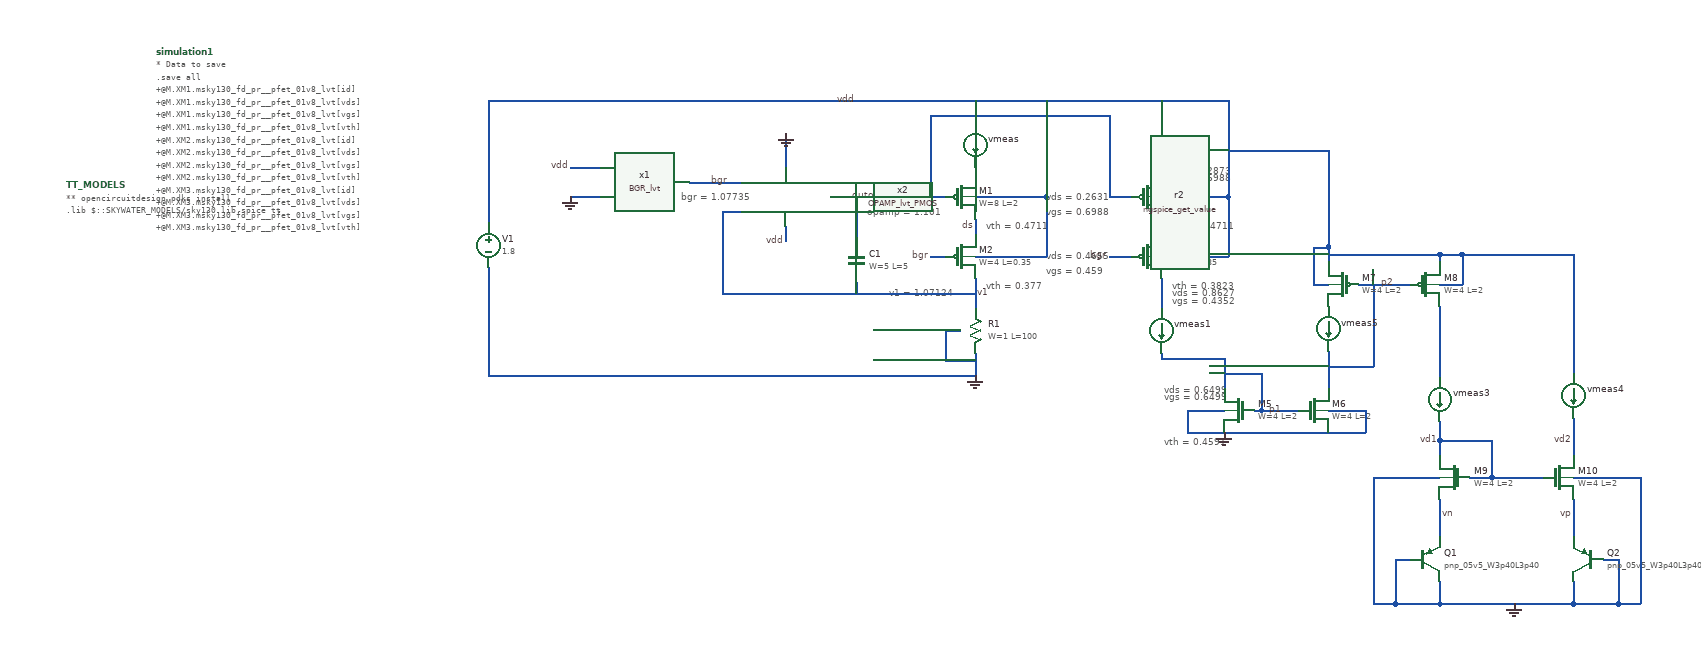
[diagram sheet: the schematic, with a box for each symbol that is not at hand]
v {xschem version=3.1.0 file_version=1.2
}
G {}
K {}
V {}
S {}
E {}
T {bgr = 1.07735} 1030 -690 0 0 0.2 0.2 {}
T {opamp = 1.101} 1280 -670 0 0 0.2 0.2 {}
T {vth = 0.4711} 1440 -650 0 0 0.2 0.2 {}
T {vth = 0.377} 1440 -570 0 0 0.2 0.2 {}
T {vth = 0.4711} 1690 -650 0 0 0.2 0.2 {}
T {vth = 0.3823} 1690 -570 0 0 0.2 0.2 {}
T {vds = 0.2631} 1520 -690 0 0 0.2 0.2 {}
T {vgs = 0.6988} 1520 -670 0 0 0.2 0.2 {}
T {vds = 0.4655} 1520 -610 0 0 0.2 0.2 {}
T {vgs = 0.459} 1520 -590 0 0 0.2 0.2 {}
T {vds = 0.2873} 1685 -725 0 0 0.2 0.2 {}
T {vgs = 0.6988} 1685 -715 0 0 0.2 0.2 {}
T {vds = 0.8627} 1690 -560 0 0 0.2 0.2 {}
T {vgs = 0.4352} 1690 -550 0 0 0.2 0.2 {}
T {v1 = 1.07124} 1310 -560 0 0 0.2 0.2 {}
T {vth = 0.4591} 1680 -360 0 0 0.2 0.2 {}
T {vgs = 0.6499} 1680 -420 0 0 0.2 0.2 {}
T {vds = 0.6499} 1680 -430 0 0 0.2 0.2 {}
N 1070 -697.5 1110 -697.5 {
lab=bgr}
N 1085 -657.5 1110 -657.5 {
lab=v1}
N 880 -677.5 890 -677.5 {
lab=GND}
N 880 -717.5 890 -717.5 {
lab=vdd}
N 1425 -722.5 1425 -707.5 {
lab=#net1}
N 1230 -677.5 1385 -677.5 {
lab=outop}
N 1425 -807.5 1425 -777.5 {
lab=vdd}
N 1425 -647.5 1425 -627.5 {
lab=ds}
N 1425 -567.5 1425 -527.5 {
lab=v1}
N 1085 -547.5 1425 -547.5 {
lab=v1}
N 1085 -657.5 1085 -547.5 {
lab=v1}
N 1265 -677.5 1265 -622.5 {
lab=outop}
N 1265 -562.5 1265 -547.5 {
lab=v1}
N 1425 -677.5 1520 -677.5 {
lab=vdd}
N 1520 -807.5 1520 -677.5 {
lab=vdd}
N 1425 -597.5 1520 -597.5 {
lab=vdd}
N 1520 -677.5 1520 -597.5 {
lab=vdd}
N 770 -437.5 1425 -437.5 {
lab=GND}
N 770 -582.5 770 -437.5 {
lab=GND}
N 1365 -597.5 1385 -597.5 {
lab=bgr}
N 1425 -467.5 1425 -437.5 {
lab=GND}
N 1170 -637.5 1170 -617.5 {
lab=vdd}
N 1170 -762.5 1170 -717.5 {
lab=GND}
N 1385 -497.5 1405 -497.5 {
lab=GND}
N 1385 -497.5 1385 -457.5 {
lab=GND}
N 1385 -457.5 1425 -457.5 {
lab=GND}
N 1365 -787.5 1365 -677.5 {
lab=outop}
N 1365 -787.5 1605 -787.5 {
lab=outop}
N 1605 -787.5 1605 -677.5 {
lab=outop}
N 1605 -677.5 1635 -677.5 {
lab=outop}
N 1605 -597.5 1635 -597.5 {
lab=bgr}
N 1675 -647.5 1675 -627.5 {
lab=#net2}
N 1675 -567.5 1675 -527.5 {
lab=#net3}
N 1675 -807.5 1675 -707.5 {
lab=vdd}
N 1675 -597.5 1765 -597.5 {
lab=vdd}
N 1765 -677.5 1765 -597.5 {
lab=vdd}
N 1675 -677.5 1765 -677.5 {
lab=vdd}
N 1765 -807.5 1765 -677.5 {
lab=vdd}
N 770 -807.5 1765 -807.5 {
lab=vdd}
N 770 -807.5 770 -642.5 {
lab=vdd}
N 890 -717.5 920 -717.5 {
lab=vdd}
N 890 -677.5 920 -677.5 {
lab=GND}
N 1040 -697.5 1070 -697.5 {
lab=bgr}
N 2120 -300 2190 -300 {
lab=vd1}
N 2050 -350 2120 -350 {
lab=vd1}
N 2120 -350 2120 -300 {
lab=vd1}
N 2050 -250 2050 -220 {
lab=vn}
N 2230 -250 2230 -220 {
lab=vp}
N 2230 -380 2230 -330 {
lab=vd2}
N 2050 -160 2050 -130 {
lab=GND}
N 2050 -130 2230 -130 {
lab=GND}
N 2230 -160 2230 -130 {
lab=GND}
N 1990 -190 2010 -190 {
lab=GND}
N 1990 -190 1990 -130 {
lab=GND}
N 1990 -130 2050 -130 {
lab=GND}
N 2270 -190 2290 -190 {
lab=GND}
N 2290 -190 2290 -130 {
lab=GND}
N 2230 -130 2290 -130 {
lab=GND}
N 1960 -300 2050 -300 {
lab=GND}
N 1960 -300 1960 -130 {
lab=GND}
N 1960 -130 1990 -130 {
lab=GND}
N 2230 -300 2320 -300 {
lab=GND}
N 2320 -300 2320 -130 {
lab=GND}
N 2290 -130 2320 -130 {
lab=GND}
N 2230 -460 2230 -440 {
lab=vdd}
N 2050 -470 2050 -435 {
lab=#net4}
N 2050 -350 2050 -330 {
lab=vd1}
N 2050 -375 2050 -350 {
lab=vd1}
N 2090 -300 2120 -300 {
lab=vd1}
N 2230 -270 2230 -250 {
lab=vp}
N 2050 -270 2050 -250 {
lab=vn}
N 1760 -460 1760 -420 {
lab=p1}
N 1760 -440 1810 -440 {
lab=p1}
N 1810 -440 1810 -390 {
lab=p1}
N 1800 -390 1810 -390 {
lab=p1}
N 1810 -390 1860 -390 {
lab=p1}
N 1760 -360 1900 -360 {
lab=GND}
N 1900 -470 1900 -420 {
lab=p2}
N 1940 -560 2010 -560 {
lab=p2}
N 1900 -450 1960 -450 {
lab=p2}
N 1960 -500 1960 -450 {
lab=p2}
N 1900 -610 1900 -590 {
lab=vdd}
N 1900 -600 2050 -600 {
lab=vdd}
N 2050 -600 2050 -590 {
lab=vdd}
N 1880 -560 1900 -560 {
lab=vdd}
N 1880 -610 1880 -560 {
lab=vdd}
N 1880 -610 1900 -610 {
lab=vdd}
N 2050 -560 2080 -560 {
lab=vdd}
N 2080 -600 2080 -560 {
lab=vdd}
N 2050 -600 2080 -600 {
lab=vdd}
N 1710 -390 1760 -390 {
lab=GND}
N 1710 -390 1710 -360 {
lab=GND}
N 1710 -360 1760 -360 {
lab=GND}
N 1900 -390 1950 -390 {
lab=GND}
N 1950 -390 1950 -360 {
lab=GND}
N 1900 -360 1950 -360 {
lab=GND}
N 1960 -560 1960 -500 {
lab=p2}
N 2050 -530 2050 -470 {
lab=#net4}
N 1675 -460 1760 -460 {
lab=p1}
N 1675 -467.5 1675 -460 {
lab=p1}
N 1765 -740 1900 -740 {
lab=vdd}
N 1900 -740 1900 -610 {
lab=vdd}
N 2230 -600 2230 -460 {
lab=vdd}
N 2080 -600 2230 -600 {
lab=vdd}
C {devices/vsource.sym} 770 -612.5 0 0 {name=V1 value=1.8}
C {devices/gnd.sym} 1425 -437.5 0 0 {name=l1 lab=GND}
C {devices/ammeter.sym} 1425 -747.5 0 0 {name=vmeas}
C {sky130_fd_pr/cap_mim_m3_1.sym} 1265 -592.5 0 1 {name=C1 model=cap_mim_m3_1 W=5 L=5 MF=1 spiceprefix=X}
C {devices/lab_pin.sym} 1265 -807.5 1 0 {name=p1 sig_type=std_logic lab=vdd}
C {devices/lab_pin.sym} 1425 -547.5 2 0 {name=p2 sig_type=std_logic lab=v1}
C {sky130_fd_pr/pfet_01v8_lvt.sym} 1405 -677.5 0 0 {name=M1
L=2
W=8
nf=1
mult=1
ad="'int((nf+1)/2) * W/nf * 0.29'" 
pd="'2*int((nf+1)/2) * (W/nf + 0.29)'"
as="'int((nf+2)/2) * W/nf * 0.29'" 
ps="'2*int((nf+2)/2) * (W/nf + 0.29)'"
nrd="'0.29 / W'" nrs="'0.29 / W'"
sa=0 sb=0 sd=0
model=pfet_01v8_lvt
spiceprefix=X
}
C {sky130_fd_pr/pfet_01v8_lvt.sym} 1405 -597.5 0 0 {name=M2
L=0.35
W=4
nf=1
mult=1
ad="'int((nf+1)/2) * W/nf * 0.29'" 
pd="'2*int((nf+1)/2) * (W/nf + 0.29)'"
as="'int((nf+2)/2) * W/nf * 0.29'" 
ps="'2*int((nf+2)/2) * (W/nf + 0.29)'"
nrd="'0.29 / W'" nrs="'0.29 / W'"
sa=0 sb=0 sd=0
model=pfet_01v8_lvt
spiceprefix=X
}
C {devices/lab_pin.sym} 1300 -677.5 1 0 {name=p3 sig_type=std_logic lab=outop}
C {devices/lab_pin.sym} 1425 -637.5 0 0 {name=p4 sig_type=std_logic lab=ds}
C {devices/lab_pin.sym} 1095 -697.5 1 0 {name=p5 sig_type=std_logic lab=bgr}
C {sky130_fd_pr/res_xhigh_po.sym} 1425 -497.5 0 0 {name=R1
W=1
L=100
model=res_xhigh_po
spiceprefix=X
mult=1}
C {sky130_fd_pr/pfet_01v8_lvt.sym} 1655 -677.5 0 0 {name=M3
L=2
W=16
nf=2
mult=1
ad="'int((nf+1)/2) * W/nf * 0.29'" 
pd="'2*int((nf+1)/2) * (W/nf + 0.29)'"
as="'int((nf+2)/2) * W/nf * 0.29'" 
ps="'2*int((nf+2)/2) * (W/nf + 0.29)'"
nrd="'0.29 / W'" nrs="'0.29 / W'"
sa=0 sb=0 sd=0
model=pfet_01v8_lvt
spiceprefix=X
}
C {sky130_fd_pr/pfet_01v8_lvt.sym} 1655 -597.5 0 0 {name=M4
L=0.35
W=4
nf=1
mult=2
ad="'int((nf+1)/2) * W/nf * 0.29'" 
pd="'2*int((nf+1)/2) * (W/nf + 0.29)'"
as="'int((nf+2)/2) * W/nf * 0.29'" 
ps="'2*int((nf+2)/2) * (W/nf + 0.29)'"
nrd="'0.29 / W'" nrs="'0.29 / W'"
sa=0 sb=0 sd=0
model=pfet_01v8_lvt
spiceprefix=X
}
C {devices/ammeter.sym} 1675 -497.5 0 0 {name=vmeas1}
C {devices/gnd.sym} 880 -677.5 0 0 {name=l3 lab=GND}
C {devices/gnd.sym} 1170 -762.5 1 0 {name=l4 lab=GND}
C {devices/lab_pin.sym} 1170 -617.5 0 0 {name=p7 sig_type=std_logic lab=vdd}
C {devices/lab_pin.sym} 880 -717.5 0 0 {name=p8 sig_type=std_logic lab=vdd}
C {devices/lab_pin.sym} 1365 -597.5 1 0 {name=p9 sig_type=std_logic lab=bgr}
C {devices/lab_pin.sym} 1605 -597.5 1 0 {name=p10 sig_type=std_logic lab=bgr}
C {Documentos/TESIS DE GRADO/WORK_IN_PROGRESS/My_xschem/BGR_lvt.sym} 980 -697.5 0 0 {name=x1}
C {Documentos/TESIS DE GRADO/WORK_IN_PROGRESS/My_xschem/OPAMP_lvt_PMOS.sym} 1160 -677.5 2 1 {name=x2}
C {devices/code_shown.sym} 322.5 -872.5 0 0 {name=simulation1 only_toplevel=false 
value="* Data to save
.save all
+@M.XM1.msky130_fd_pr__pfet_01v8_lvt[id]
+@M.XM1.msky130_fd_pr__pfet_01v8_lvt[vds]
+@M.XM1.msky130_fd_pr__pfet_01v8_lvt[vgs]
+@M.XM1.msky130_fd_pr__pfet_01v8_lvt[vth]
+@M.XM2.msky130_fd_pr__pfet_01v8_lvt[id]
+@M.XM2.msky130_fd_pr__pfet_01v8_lvt[vds]
+@M.XM2.msky130_fd_pr__pfet_01v8_lvt[vgs]
+@M.XM2.msky130_fd_pr__pfet_01v8_lvt[vth]
+@M.XM3.msky130_fd_pr__pfet_01v8_lvt[id]
+@M.XM3.msky130_fd_pr__pfet_01v8_lvt[vds]
+@M.XM3.msky130_fd_pr__pfet_01v8_lvt[vgs]
+@M.XM3.msky130_fd_pr__pfet_01v8_lvt[vth]
+@M.XM4.msky130_fd_pr__pfet_01v8_lvt[id]
+@M.XM4.msky130_fd_pr__pfet_01v8_lvt[vds]
+@M.XM4.msky130_fd_pr__pfet_01v8_lvt[vgs]
+@M.XM4.msky130_fd_pr__pfet_01v8_lvt[vth]
+@M.XM5.msky130_fd_pr__nfet_01v8_lvt[id]
+@M.XM5.msky130_fd_pr__nfet_01v8_lvt[vds]
+@M.XM5.msky130_fd_pr__nfet_01v8_lvt[vgs]
+@M.XM5.msky130_fd_pr__nfet_01v8_lvt[vth]

.op
.save all
"}
C {devices/code.sym} 202.5 -692.5 0 0 {name=TT_MODELS
only_toplevel=true
format="tcleval( @value )"
value="
** opencircuitdesign pdks install
.lib $::SKYWATER_MODELS/sky130.lib.spice tt

"
spice_ignore=false}
C {devices/launcher.sym} 415 -370 0 0 {name=h1
descr=Backannotate
 tclcommand="xschem annotate_op"}
C {devices/gnd.sym} 2150 -130 0 0 {name=l2 lab=GND}
C {sky130_fd_pr/nfet_01v8_lvt.sym} 2070 -300 0 1 {name=M9
L=2
W=4
nf=2
mult=1
ad="'int((nf+1)/2) * W/nf * 0.29'" 
pd="'2*int((nf+1)/2) * (W/nf + 0.29)'"
as="'int((nf+2)/2) * W/nf * 0.29'" 
ps="'2*int((nf+2)/2) * (W/nf + 0.29)'"
nrd="'0.29 / W'" nrs="'0.29 / W'"
sa=0 sb=0 sd=0
model=nfet_01v8_lvt
spiceprefix=X
}
C {sky130_fd_pr/pnp_05v5.sym} 2030 -190 0 0 {name=Q1
model=pnp_05v5_W3p40L3p40
m=1
spiceprefix=X
}
C {sky130_fd_pr/nfet_01v8_lvt.sym} 2210 -300 0 0 {name=M10
L=2
W=4
nf=1
mult=10
ad="'int((nf+1)/2) * W/nf * 0.29'" 
pd="'2*int((nf+1)/2) * (W/nf + 0.29)'"
as="'int((nf+2)/2) * W/nf * 0.29'" 
ps="'2*int((nf+2)/2) * (W/nf + 0.29)'"
nrd="'0.29 / W'" nrs="'0.29 / W'"
sa=0 sb=0 sd=0
model=nfet_01v8_lvt
spiceprefix=X
}
C {sky130_fd_pr/pnp_05v5.sym} 2250 -190 0 1 {name=Q2
model=pnp_05v5_W3p40L3p40
m=1
spiceprefix=X
}
C {devices/lab_pin.sym} 2230 -250 0 0 {name=p11 sig_type=std_logic lab=vp}
C {devices/lab_pin.sym} 2050 -250 2 0 {name=p12 sig_type=std_logic lab=vn}
C {devices/ammeter.sym} 2230 -410 0 0 {name=vmeas4}
C {devices/ammeter.sym} 2050 -405 0 0 {name=vmeas3}
C {devices/lab_pin.sym} 2050 -350 0 0 {name=p13 sig_type=std_logic lab=vd1}
C {devices/lab_pin.sym} 2230 -350 0 0 {name=p14 sig_type=std_logic lab=vd2}
C {devices/ngspice_get_value.sym} 2120 -310 0 0 {name=r2 node=v(@M.XM1.msky130_fd_pr__nfet_01v8_lvt[vth])
descr="vth="}
C {sky130_fd_pr/nfet_01v8_lvt.sym} 1780 -390 0 1 {name=M5
L=2
W=4
nf=1
mult=1
ad="'int((nf+1)/2) * W/nf * 0.29'" 
pd="'2*int((nf+1)/2) * (W/nf + 0.29)'"
as="'int((nf+2)/2) * W/nf * 0.29'" 
ps="'2*int((nf+2)/2) * (W/nf + 0.29)'"
nrd="'0.29 / W'" nrs="'0.29 / W'"
sa=0 sb=0 sd=0
model=nfet_01v8_lvt
spiceprefix=X
}
C {devices/gnd.sym} 1760 -360 0 0 {name=l11 lab=GND}
C {sky130_fd_pr/nfet_01v8_lvt.sym} 1880 -390 0 0 {name=M6
L=2
W=4
nf=1
mult=1
ad="'int((nf+1)/2) * W/nf * 0.29'" 
pd="'2*int((nf+1)/2) * (W/nf + 0.29)'"
as="'int((nf+2)/2) * W/nf * 0.29'" 
ps="'2*int((nf+2)/2) * (W/nf + 0.29)'"
nrd="'0.29 / W'" nrs="'0.29 / W'"
sa=0 sb=0 sd=0
model=nfet_01v8_lvt
spiceprefix=X
}
C {sky130_fd_pr/pfet_01v8_lvt.sym} 1920 -560 0 1 {name=M7
L=2
W=4
nf=1
mult=1
ad="'int((nf+1)/2) * W/nf * 0.29'" 
pd="'2*int((nf+1)/2) * (W/nf + 0.29)'"
as="'int((nf+2)/2) * W/nf * 0.29'" 
ps="'2*int((nf+2)/2) * (W/nf + 0.29)'"
nrd="'0.29 / W'" nrs="'0.29 / W'"
sa=0 sb=0 sd=0
model=pfet_01v8_lvt
spiceprefix=X
}
C {sky130_fd_pr/pfet_01v8_lvt.sym} 2030 -560 0 0 {name=M8
L=2
W=4
nf=1
mult=1
ad="'int((nf+1)/2) * W/nf * 0.29'" 
pd="'2*int((nf+1)/2) * (W/nf + 0.29)'"
as="'int((nf+2)/2) * W/nf * 0.29'" 
ps="'2*int((nf+2)/2) * (W/nf + 0.29)'"
nrd="'0.29 / W'" nrs="'0.29 / W'"
sa=0 sb=0 sd=0
model=pfet_01v8_lvt
spiceprefix=X
}
C {devices/lab_pin.sym} 1840 -390 1 0 {name=p15 sig_type=std_logic lab=p1}
C {devices/lab_pin.sym} 1990 -560 1 0 {name=p16 sig_type=std_logic lab=p2}
C {devices/ammeter.sym} 1900 -500 0 0 {name=vmeas5}
